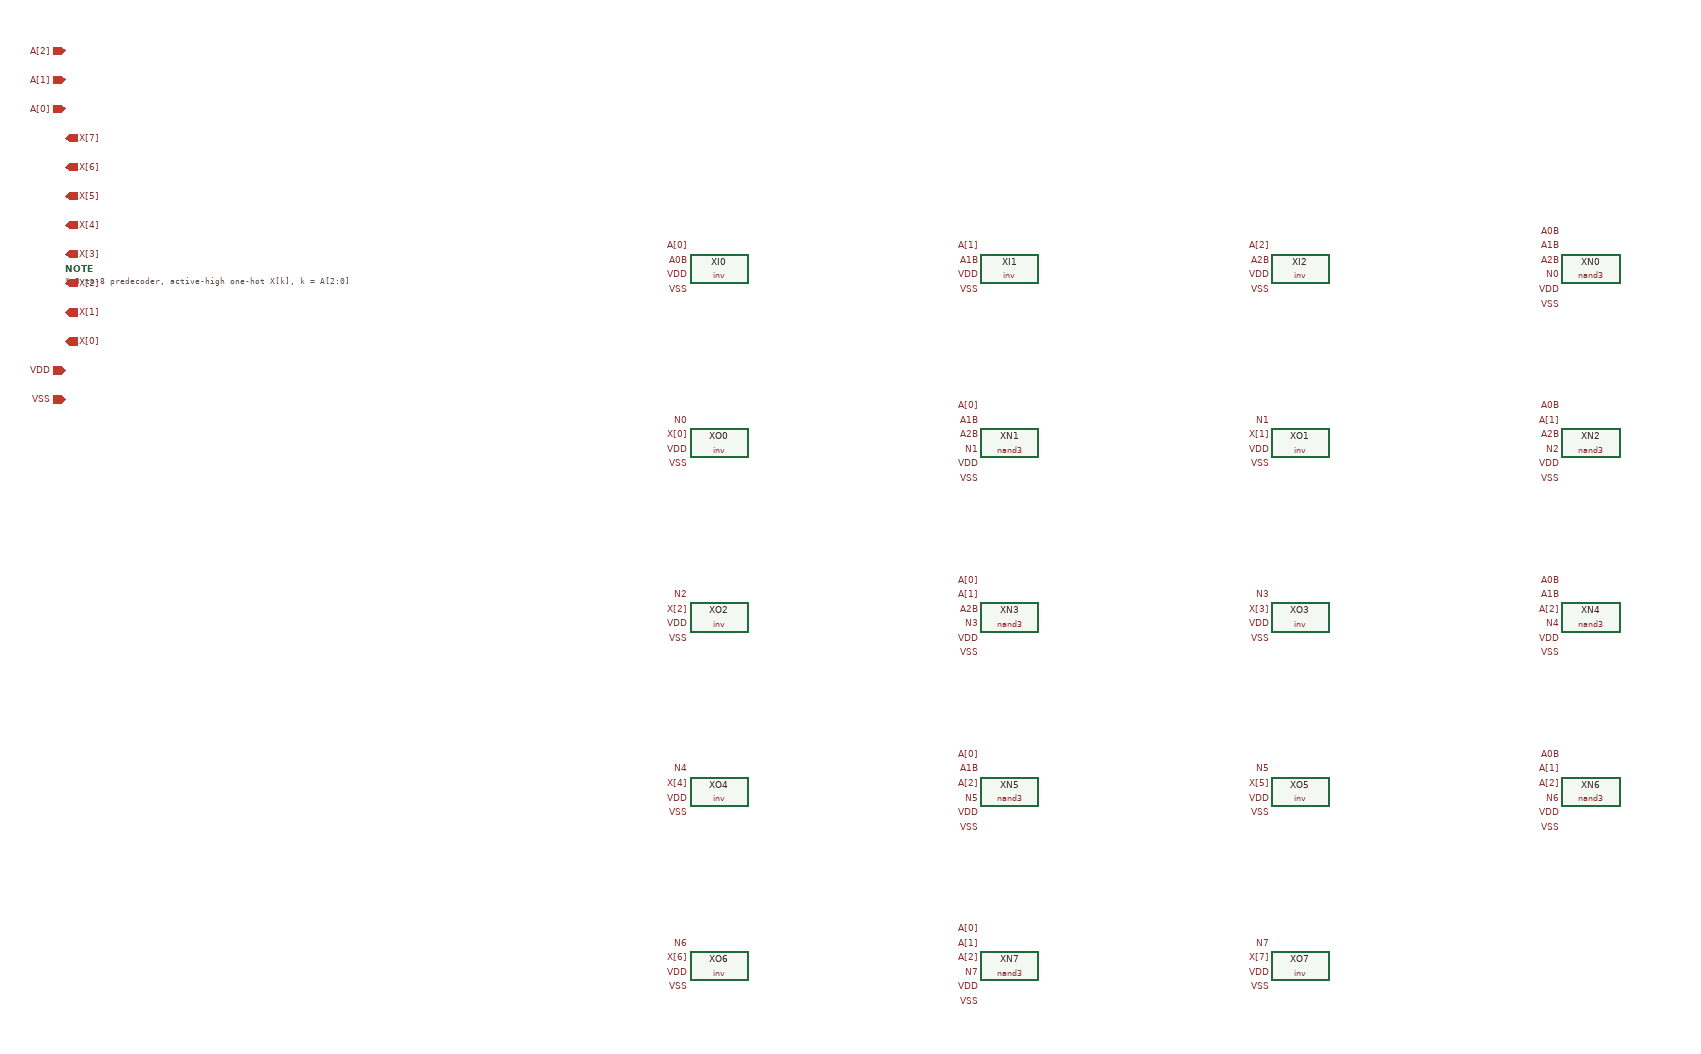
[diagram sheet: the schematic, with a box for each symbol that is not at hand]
v {xschem version=3.4.8RC file_version=1.3}
G {}
K {}
V {}
S {}
E {}
C {gates/inv.sym} 0 0 0 0 {name=XI0}
C {devices/lab_pin.sym} -40.0 -30.0 0 0 {name=l0 lab=A[0]}
C {devices/lab_pin.sym} -40.0 -10.0 0 0 {name=l1 lab=A0B}
C {devices/lab_pin.sym} -40.0 10.0 0 0 {name=l2 lab=VDD}
C {devices/lab_pin.sym} -40.0 30.0 0 0 {name=l3 lab=VSS}
C {gates/inv.sym} 400 0 0 0 {name=XI1}
C {devices/lab_pin.sym} 360.0 -30.0 0 0 {name=l4 lab=A[1]}
C {devices/lab_pin.sym} 360.0 -10.0 0 0 {name=l5 lab=A1B}
C {devices/lab_pin.sym} 360.0 10.0 0 0 {name=l6 lab=VDD}
C {devices/lab_pin.sym} 360.0 30.0 0 0 {name=l7 lab=VSS}
C {gates/inv.sym} 800 0 0 0 {name=XI2}
C {devices/lab_pin.sym} 760.0 -30.0 0 0 {name=l8 lab=A[2]}
C {devices/lab_pin.sym} 760.0 -10.0 0 0 {name=l9 lab=A2B}
C {devices/lab_pin.sym} 760.0 10.0 0 0 {name=l10 lab=VDD}
C {devices/lab_pin.sym} 760.0 30.0 0 0 {name=l11 lab=VSS}
C {gates/nand3.sym} 1200 0 0 0 {name=XN0}
C {devices/lab_pin.sym} 1160.0 -50.0 0 0 {name=l12 lab=A0B}
C {devices/lab_pin.sym} 1160.0 -30.0 0 0 {name=l13 lab=A1B}
C {devices/lab_pin.sym} 1160.0 -10.0 0 0 {name=l14 lab=A2B}
C {devices/lab_pin.sym} 1160.0 10.0 0 0 {name=l15 lab=N0}
C {devices/lab_pin.sym} 1160.0 30.0 0 0 {name=l16 lab=VDD}
C {devices/lab_pin.sym} 1160.0 50.0 0 0 {name=l17 lab=VSS}
C {gates/inv.sym} 0 240 0 0 {name=XO0}
C {devices/lab_pin.sym} -40.0 210.0 0 0 {name=l18 lab=N0}
C {devices/lab_pin.sym} -40.0 230.0 0 0 {name=l19 lab=X[0]}
C {devices/lab_pin.sym} -40.0 250.0 0 0 {name=l20 lab=VDD}
C {devices/lab_pin.sym} -40.0 270.0 0 0 {name=l21 lab=VSS}
C {gates/nand3.sym} 400 240 0 0 {name=XN1}
C {devices/lab_pin.sym} 360.0 190.0 0 0 {name=l22 lab=A[0]}
C {devices/lab_pin.sym} 360.0 210.0 0 0 {name=l23 lab=A1B}
C {devices/lab_pin.sym} 360.0 230.0 0 0 {name=l24 lab=A2B}
C {devices/lab_pin.sym} 360.0 250.0 0 0 {name=l25 lab=N1}
C {devices/lab_pin.sym} 360.0 270.0 0 0 {name=l26 lab=VDD}
C {devices/lab_pin.sym} 360.0 290.0 0 0 {name=l27 lab=VSS}
C {gates/inv.sym} 800 240 0 0 {name=XO1}
C {devices/lab_pin.sym} 760.0 210.0 0 0 {name=l28 lab=N1}
C {devices/lab_pin.sym} 760.0 230.0 0 0 {name=l29 lab=X[1]}
C {devices/lab_pin.sym} 760.0 250.0 0 0 {name=l30 lab=VDD}
C {devices/lab_pin.sym} 760.0 270.0 0 0 {name=l31 lab=VSS}
C {gates/nand3.sym} 1200 240 0 0 {name=XN2}
C {devices/lab_pin.sym} 1160.0 190.0 0 0 {name=l32 lab=A0B}
C {devices/lab_pin.sym} 1160.0 210.0 0 0 {name=l33 lab=A[1]}
C {devices/lab_pin.sym} 1160.0 230.0 0 0 {name=l34 lab=A2B}
C {devices/lab_pin.sym} 1160.0 250.0 0 0 {name=l35 lab=N2}
C {devices/lab_pin.sym} 1160.0 270.0 0 0 {name=l36 lab=VDD}
C {devices/lab_pin.sym} 1160.0 290.0 0 0 {name=l37 lab=VSS}
C {gates/inv.sym} 0 480 0 0 {name=XO2}
C {devices/lab_pin.sym} -40.0 450.0 0 0 {name=l38 lab=N2}
C {devices/lab_pin.sym} -40.0 470.0 0 0 {name=l39 lab=X[2]}
C {devices/lab_pin.sym} -40.0 490.0 0 0 {name=l40 lab=VDD}
C {devices/lab_pin.sym} -40.0 510.0 0 0 {name=l41 lab=VSS}
C {gates/nand3.sym} 400 480 0 0 {name=XN3}
C {devices/lab_pin.sym} 360.0 430.0 0 0 {name=l42 lab=A[0]}
C {devices/lab_pin.sym} 360.0 450.0 0 0 {name=l43 lab=A[1]}
C {devices/lab_pin.sym} 360.0 470.0 0 0 {name=l44 lab=A2B}
C {devices/lab_pin.sym} 360.0 490.0 0 0 {name=l45 lab=N3}
C {devices/lab_pin.sym} 360.0 510.0 0 0 {name=l46 lab=VDD}
C {devices/lab_pin.sym} 360.0 530.0 0 0 {name=l47 lab=VSS}
C {gates/inv.sym} 800 480 0 0 {name=XO3}
C {devices/lab_pin.sym} 760.0 450.0 0 0 {name=l48 lab=N3}
C {devices/lab_pin.sym} 760.0 470.0 0 0 {name=l49 lab=X[3]}
C {devices/lab_pin.sym} 760.0 490.0 0 0 {name=l50 lab=VDD}
C {devices/lab_pin.sym} 760.0 510.0 0 0 {name=l51 lab=VSS}
C {gates/nand3.sym} 1200 480 0 0 {name=XN4}
C {devices/lab_pin.sym} 1160.0 430.0 0 0 {name=l52 lab=A0B}
C {devices/lab_pin.sym} 1160.0 450.0 0 0 {name=l53 lab=A1B}
C {devices/lab_pin.sym} 1160.0 470.0 0 0 {name=l54 lab=A[2]}
C {devices/lab_pin.sym} 1160.0 490.0 0 0 {name=l55 lab=N4}
C {devices/lab_pin.sym} 1160.0 510.0 0 0 {name=l56 lab=VDD}
C {devices/lab_pin.sym} 1160.0 530.0 0 0 {name=l57 lab=VSS}
C {gates/inv.sym} 0 720 0 0 {name=XO4}
C {devices/lab_pin.sym} -40.0 690.0 0 0 {name=l58 lab=N4}
C {devices/lab_pin.sym} -40.0 710.0 0 0 {name=l59 lab=X[4]}
C {devices/lab_pin.sym} -40.0 730.0 0 0 {name=l60 lab=VDD}
C {devices/lab_pin.sym} -40.0 750.0 0 0 {name=l61 lab=VSS}
C {gates/nand3.sym} 400 720 0 0 {name=XN5}
C {devices/lab_pin.sym} 360.0 670.0 0 0 {name=l62 lab=A[0]}
C {devices/lab_pin.sym} 360.0 690.0 0 0 {name=l63 lab=A1B}
C {devices/lab_pin.sym} 360.0 710.0 0 0 {name=l64 lab=A[2]}
C {devices/lab_pin.sym} 360.0 730.0 0 0 {name=l65 lab=N5}
C {devices/lab_pin.sym} 360.0 750.0 0 0 {name=l66 lab=VDD}
C {devices/lab_pin.sym} 360.0 770.0 0 0 {name=l67 lab=VSS}
C {gates/inv.sym} 800 720 0 0 {name=XO5}
C {devices/lab_pin.sym} 760.0 690.0 0 0 {name=l68 lab=N5}
C {devices/lab_pin.sym} 760.0 710.0 0 0 {name=l69 lab=X[5]}
C {devices/lab_pin.sym} 760.0 730.0 0 0 {name=l70 lab=VDD}
C {devices/lab_pin.sym} 760.0 750.0 0 0 {name=l71 lab=VSS}
C {gates/nand3.sym} 1200 720 0 0 {name=XN6}
C {devices/lab_pin.sym} 1160.0 670.0 0 0 {name=l72 lab=A0B}
C {devices/lab_pin.sym} 1160.0 690.0 0 0 {name=l73 lab=A[1]}
C {devices/lab_pin.sym} 1160.0 710.0 0 0 {name=l74 lab=A[2]}
C {devices/lab_pin.sym} 1160.0 730.0 0 0 {name=l75 lab=N6}
C {devices/lab_pin.sym} 1160.0 750.0 0 0 {name=l76 lab=VDD}
C {devices/lab_pin.sym} 1160.0 770.0 0 0 {name=l77 lab=VSS}
C {gates/inv.sym} 0 960 0 0 {name=XO6}
C {devices/lab_pin.sym} -40.0 930.0 0 0 {name=l78 lab=N6}
C {devices/lab_pin.sym} -40.0 950.0 0 0 {name=l79 lab=X[6]}
C {devices/lab_pin.sym} -40.0 970.0 0 0 {name=l80 lab=VDD}
C {devices/lab_pin.sym} -40.0 990.0 0 0 {name=l81 lab=VSS}
C {gates/nand3.sym} 400 960 0 0 {name=XN7}
C {devices/lab_pin.sym} 360.0 910.0 0 0 {name=l82 lab=A[0]}
C {devices/lab_pin.sym} 360.0 930.0 0 0 {name=l83 lab=A[1]}
C {devices/lab_pin.sym} 360.0 950.0 0 0 {name=l84 lab=A[2]}
C {devices/lab_pin.sym} 360.0 970.0 0 0 {name=l85 lab=N7}
C {devices/lab_pin.sym} 360.0 990.0 0 0 {name=l86 lab=VDD}
C {devices/lab_pin.sym} 360.0 1010.0 0 0 {name=l87 lab=VSS}
C {gates/inv.sym} 800 960 0 0 {name=XO7}
C {devices/lab_pin.sym} 760.0 930.0 0 0 {name=l88 lab=N7}
C {devices/lab_pin.sym} 760.0 950.0 0 0 {name=l89 lab=X[7]}
C {devices/lab_pin.sym} 760.0 970.0 0 0 {name=l90 lab=VDD}
C {devices/lab_pin.sym} 760.0 990.0 0 0 {name=l91 lab=VSS}
C {devices/ipin.sym} -900 -300 0 0 {name=p92 lab=A[2]}
C {devices/ipin.sym} -900 -260 0 0 {name=p93 lab=A[1]}
C {devices/ipin.sym} -900 -220 0 0 {name=p94 lab=A[0]}
C {devices/opin.sym} -900 -180 0 0 {name=p95 lab=X[7]}
C {devices/opin.sym} -900 -140 0 0 {name=p96 lab=X[6]}
C {devices/opin.sym} -900 -100 0 0 {name=p97 lab=X[5]}
C {devices/opin.sym} -900 -60 0 0 {name=p98 lab=X[4]}
C {devices/opin.sym} -900 -20 0 0 {name=p99 lab=X[3]}
C {devices/opin.sym} -900 20 0 0 {name=p100 lab=X[2]}
C {devices/opin.sym} -900 60 0 0 {name=p101 lab=X[1]}
C {devices/opin.sym} -900 100 0 0 {name=p102 lab=X[0]}
C {devices/iopin.sym} -900 140 0 0 {name=p103 lab=VDD}
C {devices/iopin.sym} -900 180 0 0 {name=p104 lab=VSS}
C {devices/code_shown.sym} -900 0 0 0 {name=NOTE only_toplevel=false
place=header
value="* 3-to-8 predecoder, active-high one-hot X[k], k = A[2:0]"}
